VERSION 5.7 ;
  NOWIREEXTENSIONATPIN ON ;
  DIVIDERCHAR "/" ;
  BUSBITCHARS "[]" ;
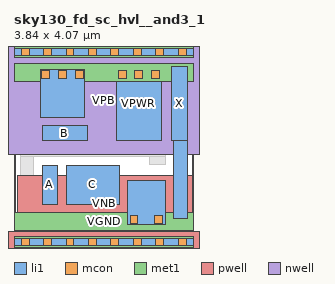
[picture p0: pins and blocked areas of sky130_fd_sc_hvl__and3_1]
MACRO sky130_fd_sc_hvl__and3_1
  CLASS BLOCK ;
  FOREIGN sky130_fd_sc_hvl__and3_1 ;
  ORIGIN 0.000 0.000 ;
  SIZE 3.840 BY 4.070 ;
  PIN A
    ANTENNAGATEAREA 0.420000 ;
    PORT
      LAYER li1 ;
        RECT 0.605 0.810 0.935 1.645 ;
    END
  END A
  PIN B
    ANTENNAGATEAREA 0.420000 ;
    PORT
      LAYER li1 ;
        RECT 0.605 2.175 1.565 2.490 ;
    END
  END B
  PIN C
    ANTENNAGATEAREA 0.420000 ;
    PORT
      LAYER li1 ;
        RECT 1.115 0.810 2.255 1.645 ;
    END
  END C
  PIN VGND
    USE GROUND ;
    PORT
      LAYER li1 ;
        RECT 2.435 0.365 3.240 1.325 ;
      LAYER mcon ;
        RECT 2.485 0.395 2.655 0.565 ;
        RECT 3.015 0.395 3.185 0.565 ;
      LAYER met1 ;
        RECT 0.000 0.255 3.840 0.625 ;
    END
  END VGND
  PIN VNB
    ANTENNADIFFAREA 0.652800 ;
    PORT
      LAYER pwell ;
        RECT 0.065 0.215 3.820 1.415 ;
        RECT -0.130 -0.215 3.970 0.215 ;
      LAYER li1 ;
        RECT 0.000 -0.085 3.840 0.085 ;
      LAYER mcon ;
        RECT 0.155 -0.085 0.325 0.085 ;
        RECT 0.635 -0.085 0.805 0.085 ;
        RECT 1.115 -0.085 1.285 0.085 ;
        RECT 1.595 -0.085 1.765 0.085 ;
        RECT 2.075 -0.085 2.245 0.085 ;
        RECT 2.555 -0.085 2.725 0.085 ;
        RECT 3.035 -0.085 3.205 0.085 ;
        RECT 3.515 -0.085 3.685 0.085 ;
      LAYER met1 ;
        RECT 0.000 -0.115 3.840 0.115 ;
    END
  END VNB
  PIN VPB
    ANTENNADIFFAREA 0.652800 ;
    PORT
      LAYER nwell ;
        RECT -0.330 1.885 4.170 4.485 ;
      LAYER li1 ;
        RECT 0.000 3.985 3.840 4.155 ;
      LAYER mcon ;
        RECT 0.155 3.985 0.325 4.155 ;
        RECT 0.635 3.985 0.805 4.155 ;
        RECT 1.115 3.985 1.285 4.155 ;
        RECT 1.595 3.985 1.765 4.155 ;
        RECT 2.075 3.985 2.245 4.155 ;
        RECT 2.555 3.985 2.725 4.155 ;
        RECT 3.035 3.985 3.205 4.155 ;
        RECT 3.515 3.985 3.685 4.155 ;
      LAYER met1 ;
        RECT 0.000 3.955 3.840 4.185 ;
    END
  END VPB
  PIN VPWR
    USE POWER ;
    PORT
      LAYER li1 ;
        RECT 0.560 2.670 1.510 3.705 ;
        RECT 2.200 2.175 3.150 3.755 ;
      LAYER mcon ;
        RECT 0.590 3.505 0.760 3.675 ;
        RECT 0.950 3.505 1.120 3.675 ;
        RECT 1.310 3.505 1.480 3.675 ;
        RECT 2.230 3.505 2.400 3.675 ;
        RECT 2.590 3.505 2.760 3.675 ;
        RECT 2.950 3.505 3.120 3.675 ;
      LAYER met1 ;
        RECT 0.000 3.445 3.840 3.815 ;
    END
  END VPWR
  PIN X
    ANTENNADIFFAREA 0.626250 ;
    PORT
      LAYER li1 ;
        RECT 3.365 2.175 3.715 3.755 ;
        RECT 3.410 0.495 3.715 2.175 ;
    END
  END X
  OBS
      LAYER li1 ;
        RECT 0.130 1.995 0.380 3.045 ;
        RECT 1.770 1.995 2.020 3.045 ;
        RECT 0.130 1.825 3.240 1.995 ;
        RECT 0.130 0.825 0.425 1.825 ;
        RECT 2.910 1.665 3.240 1.825 ;
  END
END sky130_fd_sc_hvl__and3_1
END LIBRARY

